VERSION 5.7 ;
  NOWIREEXTENSIONATPIN ON ;
  DIVIDERCHAR "/" ;
  BUSBITCHARS "[]" ;
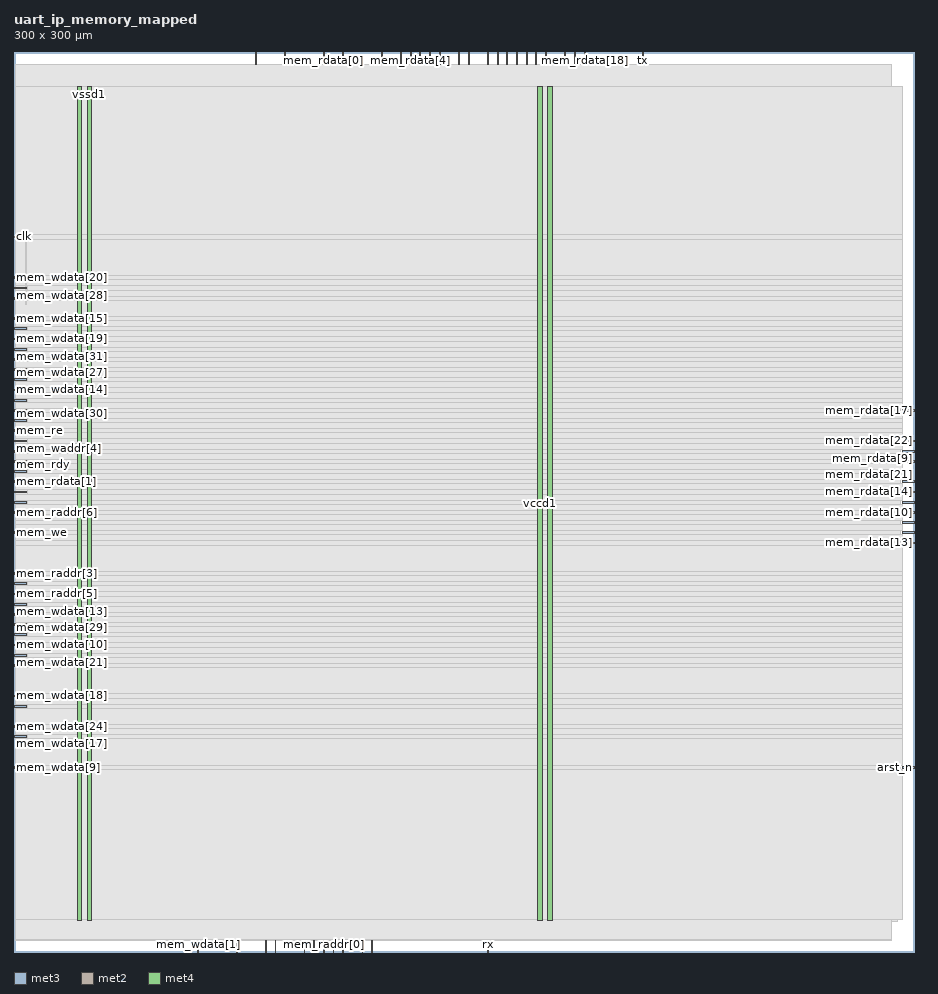
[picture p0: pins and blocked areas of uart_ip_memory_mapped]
MACRO uart_ip_memory_mapped
  CLASS BLOCK ;
  FOREIGN uart_ip_memory_mapped ;
  ORIGIN 0.000 0.000 ;
  SIZE 300.000 BY 300.000 ;
  PIN arst_n
    DIRECTION INPUT ;
    USE SIGNAL ;
    ANTENNAGATEAREA 0.682200 ;
    ANTENNADIFFAREA 0.434700 ;
    PORT
      LAYER met3 ;
        RECT 296.000 61.240 300.000 61.840 ;
    END
  END arst_n
  PIN clk
    DIRECTION INPUT ;
    USE SIGNAL ;
    ANTENNAGATEAREA 1.286700 ;
    ANTENNADIFFAREA 0.434700 ;
    PORT
      LAYER met3 ;
        RECT 0.000 238.040 4.000 238.640 ;
    END
  END clk
  PIN mem_raddr[0]
    DIRECTION OUTPUT ;
    USE SIGNAL ;
    ANTENNADIFFAREA 0.340600 ;
    PORT
      LAYER met2 ;
        RECT 103.130 0.000 103.410 4.000 ;
    END
  END mem_raddr[0]
  PIN mem_raddr[1]
    DIRECTION OUTPUT ;
    USE SIGNAL ;
    ANTENNADIFFAREA 0.340600 ;
    PORT
      LAYER met2 ;
        RECT 119.230 0.000 119.510 4.000 ;
    END
  END mem_raddr[1]
  PIN mem_raddr[2]
    DIRECTION OUTPUT ;
    USE SIGNAL ;
    ANTENNADIFFAREA 0.340600 ;
    PORT
      LAYER met2 ;
        RECT 109.570 0.000 109.850 4.000 ;
    END
  END mem_raddr[2]
  PIN mem_raddr[3]
    DIRECTION OUTPUT ;
    USE SIGNAL ;
    ANTENNADIFFAREA 0.340600 ;
    PORT
      LAYER met3 ;
        RECT 0.000 125.840 4.000 126.440 ;
    END
  END mem_raddr[3]
  PIN mem_raddr[4]
    DIRECTION OUTPUT ;
    USE SIGNAL ;
    ANTENNADIFFAREA 0.340600 ;
    PORT
      LAYER met3 ;
        RECT 0.000 149.640 4.000 150.240 ;
    END
  END mem_raddr[4]
  PIN mem_raddr[5]
    DIRECTION OUTPUT ;
    USE SIGNAL ;
    ANTENNADIFFAREA 0.340600 ;
    PORT
      LAYER met3 ;
        RECT 0.000 119.040 4.000 119.640 ;
    END
  END mem_raddr[5]
  PIN mem_raddr[6]
    DIRECTION OUTPUT ;
    USE SIGNAL ;
    ANTENNADIFFAREA 0.340600 ;
    PORT
      LAYER met3 ;
        RECT 0.000 146.240 4.000 146.840 ;
    END
  END mem_raddr[6]
  PIN mem_raddr[7]
    DIRECTION OUTPUT ;
    USE SIGNAL ;
    ANTENNADIFFAREA 0.340600 ;
    PORT
      LAYER met3 ;
        RECT 0.000 166.640 4.000 167.240 ;
    END
  END mem_raddr[7]
  PIN mem_rdata[0]
    DIRECTION INPUT ;
    USE SIGNAL ;
    ANTENNAGATEAREA 0.631200 ;
    ANTENNADIFFAREA 0.434700 ;
    PORT
      LAYER met2 ;
        RECT 103.130 296.000 103.410 300.000 ;
    END
  END mem_rdata[0]
  PIN mem_rdata[10]
    DIRECTION INPUT ;
    USE SIGNAL ;
    ANTENNAGATEAREA 0.631200 ;
    ANTENNADIFFAREA 0.434700 ;
    PORT
      LAYER met3 ;
        RECT 296.000 146.240 300.000 146.840 ;
    END
  END mem_rdata[10]
  PIN mem_rdata[11]
    DIRECTION INPUT ;
    USE SIGNAL ;
    ANTENNAGATEAREA 0.631200 ;
    ANTENNADIFFAREA 0.434700 ;
    PORT
      LAYER met2 ;
        RECT 161.090 296.000 161.370 300.000 ;
    END
  END mem_rdata[11]
  PIN mem_rdata[12]
    DIRECTION INPUT ;
    USE SIGNAL ;
    ANTENNAGATEAREA 0.631200 ;
    ANTENNADIFFAREA 0.434700 ;
    PORT
      LAYER met2 ;
        RECT 157.870 296.000 158.150 300.000 ;
    END
  END mem_rdata[12]
  PIN mem_rdata[13]
    DIRECTION INPUT ;
    USE SIGNAL ;
    ANTENNAGATEAREA 0.631200 ;
    ANTENNADIFFAREA 0.434700 ;
    PORT
      LAYER met3 ;
        RECT 296.000 136.040 300.000 136.640 ;
    END
  END mem_rdata[13]
  PIN mem_rdata[14]
    DIRECTION INPUT ;
    USE SIGNAL ;
    ANTENNAGATEAREA 0.631200 ;
    ANTENNADIFFAREA 0.434700 ;
    PORT
      LAYER met3 ;
        RECT 296.000 153.040 300.000 153.640 ;
    END
  END mem_rdata[14]
  PIN mem_rdata[15]
    DIRECTION INPUT ;
    USE SIGNAL ;
    ANTENNAGATEAREA 0.631200 ;
    ANTENNADIFFAREA 0.434700 ;
    PORT
      LAYER met2 ;
        RECT 151.430 296.000 151.710 300.000 ;
    END
  END mem_rdata[15]
  PIN mem_rdata[16]
    DIRECTION INPUT ;
    USE SIGNAL ;
    ANTENNAGATEAREA 0.631200 ;
    ANTENNADIFFAREA 0.434700 ;
    PORT
      LAYER met2 ;
        RECT 122.450 296.000 122.730 300.000 ;
    END
  END mem_rdata[16]
  PIN mem_rdata[17]
    DIRECTION INPUT ;
    USE SIGNAL ;
    ANTENNAGATEAREA 0.631200 ;
    ANTENNADIFFAREA 0.434700 ;
    PORT
      LAYER met3 ;
        RECT 296.000 180.240 300.000 180.840 ;
    END
  END mem_rdata[17]
  PIN mem_rdata[18]
    DIRECTION INPUT ;
    USE SIGNAL ;
    ANTENNAGATEAREA 0.631200 ;
    ANTENNADIFFAREA 0.434700 ;
    PORT
      LAYER met2 ;
        RECT 190.070 296.000 190.350 300.000 ;
    END
  END mem_rdata[18]
  PIN mem_rdata[19]
    DIRECTION INPUT ;
    USE SIGNAL ;
    ANTENNAGATEAREA 0.631200 ;
    ANTENNADIFFAREA 0.434700 ;
    PORT
      LAYER met2 ;
        RECT 164.310 296.000 164.590 300.000 ;
    END
  END mem_rdata[19]
  PIN mem_rdata[1]
    DIRECTION INPUT ;
    USE SIGNAL ;
    ANTENNAGATEAREA 0.631200 ;
    ANTENNADIFFAREA 0.434700 ;
    PORT
      LAYER met3 ;
        RECT 0.000 156.440 4.000 157.040 ;
    END
  END mem_rdata[1]
  PIN mem_rdata[20]
    DIRECTION INPUT ;
    USE SIGNAL ;
    ANTENNAGATEAREA 0.631200 ;
    ANTENNADIFFAREA 0.434700 ;
    PORT
      LAYER met2 ;
        RECT 170.750 296.000 171.030 300.000 ;
    END
  END mem_rdata[20]
  PIN mem_rdata[21]
    DIRECTION INPUT ;
    USE SIGNAL ;
    ANTENNAGATEAREA 0.631200 ;
    ANTENNADIFFAREA 0.434700 ;
    PORT
      LAYER met3 ;
        RECT 296.000 156.440 300.000 157.040 ;
    END
  END mem_rdata[21]
  PIN mem_rdata[22]
    DIRECTION INPUT ;
    USE SIGNAL ;
    ANTENNAGATEAREA 0.631200 ;
    ANTENNADIFFAREA 0.434700 ;
    PORT
      LAYER met3 ;
        RECT 296.000 170.040 300.000 170.640 ;
    END
  END mem_rdata[22]
  PIN mem_rdata[23]
    DIRECTION INPUT ;
    USE SIGNAL ;
    ANTENNAGATEAREA 0.631200 ;
    ANTENNADIFFAREA 0.434700 ;
    PORT
      LAYER met2 ;
        RECT 141.770 296.000 142.050 300.000 ;
    END
  END mem_rdata[23]
  PIN mem_rdata[24]
    DIRECTION INPUT ;
    USE SIGNAL ;
    ANTENNAGATEAREA 0.631200 ;
    ANTENNADIFFAREA 0.434700 ;
    PORT
      LAYER met2 ;
        RECT 128.890 296.000 129.170 300.000 ;
    END
  END mem_rdata[24]
  PIN mem_rdata[25]
    DIRECTION INPUT ;
    USE SIGNAL ;
    ANTENNAGATEAREA 0.631200 ;
    ANTENNADIFFAREA 0.434700 ;
    PORT
      LAYER met2 ;
        RECT 183.630 296.000 183.910 300.000 ;
    END
  END mem_rdata[25]
  PIN mem_rdata[26]
    DIRECTION INPUT ;
    USE SIGNAL ;
    ANTENNAGATEAREA 0.631200 ;
    ANTENNADIFFAREA 0.434700 ;
    PORT
      LAYER met2 ;
        RECT 186.850 296.000 187.130 300.000 ;
    END
  END mem_rdata[26]
  PIN mem_rdata[27]
    DIRECTION INPUT ;
    USE SIGNAL ;
    ANTENNAGATEAREA 0.631200 ;
    ANTENNADIFFAREA 0.434700 ;
    PORT
      LAYER met2 ;
        RECT 167.530 296.000 167.810 300.000 ;
    END
  END mem_rdata[27]
  PIN mem_rdata[28]
    DIRECTION INPUT ;
    USE SIGNAL ;
    ANTENNAGATEAREA 0.631200 ;
    ANTENNADIFFAREA 0.434700 ;
    PORT
      LAYER met2 ;
        RECT 173.970 296.000 174.250 300.000 ;
    END
  END mem_rdata[28]
  PIN mem_rdata[29]
    DIRECTION INPUT ;
    USE SIGNAL ;
    ANTENNAGATEAREA 0.631200 ;
    ANTENNADIFFAREA 0.434700 ;
    PORT
      LAYER met3 ;
        RECT 296.000 163.240 300.000 163.840 ;
    END
  END mem_rdata[29]
  PIN mem_rdata[2]
    DIRECTION INPUT ;
    USE SIGNAL ;
    ANTENNAGATEAREA 0.631200 ;
    ANTENNADIFFAREA 0.434700 ;
    PORT
      LAYER met3 ;
        RECT 296.000 142.840 300.000 143.440 ;
    END
  END mem_rdata[2]
  PIN mem_rdata[30]
    DIRECTION INPUT ;
    USE SIGNAL ;
    ANTENNAGATEAREA 0.631200 ;
    ANTENNADIFFAREA 0.434700 ;
    PORT
      LAYER met2 ;
        RECT 177.190 296.000 177.470 300.000 ;
    END
  END mem_rdata[30]
  PIN mem_rdata[31]
    DIRECTION INPUT ;
    USE SIGNAL ;
    ANTENNAGATEAREA 0.631200 ;
    ANTENNADIFFAREA 0.434700 ;
    PORT
      LAYER met2 ;
        RECT 138.550 296.000 138.830 300.000 ;
    END
  END mem_rdata[31]
  PIN mem_rdata[3]
    DIRECTION INPUT ;
    USE SIGNAL ;
    ANTENNAGATEAREA 0.631200 ;
    ANTENNADIFFAREA 0.434700 ;
    PORT
      LAYER met2 ;
        RECT 135.330 296.000 135.610 300.000 ;
    END
  END mem_rdata[3]
  PIN mem_rdata[4]
    DIRECTION INPUT ;
    USE SIGNAL ;
    ANTENNAGATEAREA 0.631200 ;
    ANTENNADIFFAREA 0.434700 ;
    PORT
      LAYER met2 ;
        RECT 132.110 296.000 132.390 300.000 ;
    END
  END mem_rdata[4]
  PIN mem_rdata[5]
    DIRECTION INPUT ;
    USE SIGNAL ;
    ANTENNAGATEAREA 0.631200 ;
    ANTENNADIFFAREA 0.434700 ;
    PORT
      LAYER met3 ;
        RECT 296.000 139.440 300.000 140.040 ;
    END
  END mem_rdata[5]
  PIN mem_rdata[6]
    DIRECTION INPUT ;
    USE SIGNAL ;
    ANTENNAGATEAREA 0.631200 ;
    ANTENNADIFFAREA 0.434700 ;
    PORT
      LAYER met3 ;
        RECT 296.000 149.640 300.000 150.240 ;
    END
  END mem_rdata[6]
  PIN mem_rdata[7]
    DIRECTION INPUT ;
    USE SIGNAL ;
    ANTENNAGATEAREA 0.631200 ;
    ANTENNADIFFAREA 0.434700 ;
    PORT
      LAYER met2 ;
        RECT 148.210 296.000 148.490 300.000 ;
    END
  END mem_rdata[7]
  PIN mem_rdata[8]
    DIRECTION INPUT ;
    USE SIGNAL ;
    ANTENNAGATEAREA 0.631200 ;
    ANTENNADIFFAREA 0.434700 ;
    PORT
      LAYER met2 ;
        RECT 109.570 296.000 109.850 300.000 ;
    END
  END mem_rdata[8]
  PIN mem_rdata[9]
    DIRECTION INPUT ;
    USE SIGNAL ;
    ANTENNAGATEAREA 0.631200 ;
    ANTENNADIFFAREA 0.434700 ;
    PORT
      LAYER met3 ;
        RECT 296.000 166.640 300.000 167.240 ;
    END
  END mem_rdata[9]
  PIN mem_rdy
    DIRECTION INPUT ;
    USE SIGNAL ;
    ANTENNAGATEAREA 0.631200 ;
    ANTENNADIFFAREA 0.434700 ;
    PORT
      LAYER met3 ;
        RECT 0.000 159.840 4.000 160.440 ;
    END
  END mem_rdy
  PIN mem_re
    DIRECTION OUTPUT ;
    USE SIGNAL ;
    ANTENNADIFFAREA 0.340600 ;
    PORT
      LAYER met3 ;
        RECT 0.000 173.440 4.000 174.040 ;
    END
  END mem_re
  PIN mem_waddr[0]
    DIRECTION OUTPUT ;
    USE SIGNAL ;
    ANTENNADIFFAREA 0.340600 ;
    PORT
      LAYER met2 ;
        RECT 106.350 0.000 106.630 4.000 ;
    END
  END mem_waddr[0]
  PIN mem_waddr[1]
    DIRECTION OUTPUT ;
    USE SIGNAL ;
    ANTENNADIFFAREA 0.340600 ;
    PORT
      LAYER met2 ;
        RECT 116.010 0.000 116.290 4.000 ;
    END
  END mem_waddr[1]
  PIN mem_waddr[2]
    DIRECTION OUTPUT ;
    USE SIGNAL ;
    ANTENNADIFFAREA 0.340600 ;
    PORT
      LAYER met2 ;
        RECT 96.690 0.000 96.970 4.000 ;
    END
  END mem_waddr[2]
  PIN mem_waddr[3]
    DIRECTION OUTPUT ;
    USE SIGNAL ;
    ANTENNADIFFAREA 0.340600 ;
    PORT
      LAYER met3 ;
        RECT 0.000 122.440 4.000 123.040 ;
    END
  END mem_waddr[3]
  PIN mem_waddr[4]
    DIRECTION OUTPUT ;
    USE SIGNAL ;
    ANTENNADIFFAREA 0.340600 ;
    PORT
      LAYER met3 ;
        RECT 0.000 170.040 4.000 170.640 ;
    END
  END mem_waddr[4]
  PIN mem_waddr[5]
    DIRECTION OUTPUT ;
    USE SIGNAL ;
    ANTENNADIFFAREA 0.340600 ;
    PORT
      LAYER met3 ;
        RECT 0.000 112.240 4.000 112.840 ;
    END
  END mem_waddr[5]
  PIN mem_waddr[6]
    DIRECTION OUTPUT ;
    USE SIGNAL ;
    ANTENNADIFFAREA 0.340600 ;
    PORT
      LAYER met3 ;
        RECT 0.000 153.040 4.000 153.640 ;
    END
  END mem_waddr[6]
  PIN mem_waddr[7]
    DIRECTION OUTPUT ;
    USE SIGNAL ;
    ANTENNADIFFAREA 0.340600 ;
    PORT
      LAYER met3 ;
        RECT 0.000 163.240 4.000 163.840 ;
    END
  END mem_waddr[7]
  PIN mem_wdata[0]
    DIRECTION OUTPUT ;
    USE SIGNAL ;
    ANTENNADIFFAREA 0.340600 ;
    PORT
      LAYER met2 ;
        RECT 99.910 0.000 100.190 4.000 ;
    END
  END mem_wdata[0]
  PIN mem_wdata[10]
    DIRECTION OUTPUT ;
    USE SIGNAL ;
    ANTENNADIFFAREA 0.340600 ;
    PORT
      LAYER met3 ;
        RECT 0.000 102.040 4.000 102.640 ;
    END
  END mem_wdata[10]
  PIN mem_wdata[11]
    DIRECTION OUTPUT ;
    USE SIGNAL ;
    ANTENNADIFFAREA 0.340600 ;
    PORT
      LAYER met3 ;
        RECT 0.000 217.640 4.000 218.240 ;
    END
  END mem_wdata[11]
  PIN mem_wdata[12]
    DIRECTION OUTPUT ;
    USE SIGNAL ;
    ANTENNADIFFAREA 0.340600 ;
    PORT
      LAYER met2 ;
        RECT 80.590 296.000 80.870 300.000 ;
    END
  END mem_wdata[12]
  PIN mem_wdata[13]
    DIRECTION OUTPUT ;
    USE SIGNAL ;
    ANTENNADIFFAREA 0.340600 ;
    PORT
      LAYER met3 ;
        RECT 0.000 115.640 4.000 116.240 ;
    END
  END mem_wdata[13]
  PIN mem_wdata[14]
    DIRECTION OUTPUT ;
    USE SIGNAL ;
    ANTENNADIFFAREA 0.340600 ;
    PORT
      LAYER met3 ;
        RECT 0.000 187.040 4.000 187.640 ;
    END
  END mem_wdata[14]
  PIN mem_wdata[15]
    DIRECTION OUTPUT ;
    USE SIGNAL ;
    ANTENNADIFFAREA 0.340600 ;
    PORT
      LAYER met3 ;
        RECT 0.000 210.840 4.000 211.440 ;
    END
  END mem_wdata[15]
  PIN mem_wdata[16]
    DIRECTION OUTPUT ;
    USE SIGNAL ;
    ANTENNADIFFAREA 0.340600 ;
    PORT
      LAYER met2 ;
        RECT 74.150 0.000 74.430 4.000 ;
    END
  END mem_wdata[16]
  PIN mem_wdata[17]
    DIRECTION OUTPUT ;
    USE SIGNAL ;
    ANTENNADIFFAREA 0.340600 ;
    PORT
      LAYER met3 ;
        RECT 0.000 71.440 4.000 72.040 ;
    END
  END mem_wdata[17]
  PIN mem_wdata[18]
    DIRECTION OUTPUT ;
    USE SIGNAL ;
    ANTENNADIFFAREA 0.340600 ;
    PORT
      LAYER met3 ;
        RECT 0.000 85.040 4.000 85.640 ;
    END
  END mem_wdata[18]
  PIN mem_wdata[19]
    DIRECTION OUTPUT ;
    USE SIGNAL ;
    ANTENNADIFFAREA 0.340600 ;
    PORT
      LAYER met3 ;
        RECT 0.000 204.040 4.000 204.640 ;
    END
  END mem_wdata[19]
  PIN mem_wdata[1]
    DIRECTION OUTPUT ;
    USE SIGNAL ;
    ANTENNADIFFAREA 0.340600 ;
    PORT
      LAYER met2 ;
        RECT 61.270 0.000 61.550 4.000 ;
    END
  END mem_wdata[1]
  PIN mem_wdata[20]
    DIRECTION OUTPUT ;
    USE SIGNAL ;
    ANTENNADIFFAREA 0.340600 ;
    PORT
      LAYER met3 ;
        RECT 0.000 224.440 4.000 225.040 ;
    END
  END mem_wdata[20]
  PIN mem_wdata[21]
    DIRECTION OUTPUT ;
    USE SIGNAL ;
    ANTENNADIFFAREA 0.340600 ;
    PORT
      LAYER met3 ;
        RECT 0.000 98.640 4.000 99.240 ;
    END
  END mem_wdata[21]
  PIN mem_wdata[22]
    DIRECTION OUTPUT ;
    USE SIGNAL ;
    ANTENNADIFFAREA 0.340600 ;
    PORT
      LAYER met3 ;
        RECT 0.000 183.640 4.000 184.240 ;
    END
  END mem_wdata[22]
  PIN mem_wdata[23]
    DIRECTION OUTPUT ;
    USE SIGNAL ;
    ANTENNADIFFAREA 0.340600 ;
    PORT
      LAYER met3 ;
        RECT 0.000 207.440 4.000 208.040 ;
    END
  END mem_wdata[23]
  PIN mem_wdata[24]
    DIRECTION OUTPUT ;
    USE SIGNAL ;
    ANTENNADIFFAREA 0.340600 ;
    PORT
      LAYER met3 ;
        RECT 0.000 74.840 4.000 75.440 ;
    END
  END mem_wdata[24]
  PIN mem_wdata[25]
    DIRECTION OUTPUT ;
    USE SIGNAL ;
    ANTENNADIFFAREA 0.340600 ;
    PORT
      LAYER met3 ;
        RECT 0.000 81.640 4.000 82.240 ;
    END
  END mem_wdata[25]
  PIN mem_wdata[26]
    DIRECTION OUTPUT ;
    USE SIGNAL ;
    ANTENNADIFFAREA 0.340600 ;
    PORT
      LAYER met3 ;
        RECT 0.000 95.240 4.000 95.840 ;
    END
  END mem_wdata[26]
  PIN mem_wdata[27]
    DIRECTION OUTPUT ;
    USE SIGNAL ;
    ANTENNADIFFAREA 0.340600 ;
    PORT
      LAYER met3 ;
        RECT 0.000 190.440 4.000 191.040 ;
    END
  END mem_wdata[27]
  PIN mem_wdata[28]
    DIRECTION OUTPUT ;
    USE SIGNAL ;
    ANTENNADIFFAREA 0.340600 ;
    PORT
      LAYER met3 ;
        RECT 0.000 221.040 4.000 221.640 ;
    END
  END mem_wdata[28]
  PIN mem_wdata[29]
    DIRECTION OUTPUT ;
    USE SIGNAL ;
    ANTENNADIFFAREA 0.340600 ;
    PORT
      LAYER met3 ;
        RECT 0.000 105.440 4.000 106.040 ;
    END
  END mem_wdata[29]
  PIN mem_wdata[2]
    DIRECTION OUTPUT ;
    USE SIGNAL ;
    ANTENNADIFFAREA 0.340600 ;
    PORT
      LAYER met2 ;
        RECT 87.030 0.000 87.310 4.000 ;
    END
  END mem_wdata[2]
  PIN mem_wdata[30]
    DIRECTION OUTPUT ;
    USE SIGNAL ;
    ANTENNADIFFAREA 0.340600 ;
    PORT
      LAYER met3 ;
        RECT 0.000 176.840 4.000 177.440 ;
    END
  END mem_wdata[30]
  PIN mem_wdata[31]
    DIRECTION OUTPUT ;
    USE SIGNAL ;
    ANTENNADIFFAREA 0.340600 ;
    PORT
      LAYER met3 ;
        RECT 0.000 200.640 4.000 201.240 ;
    END
  END mem_wdata[31]
  PIN mem_wdata[3]
    DIRECTION OUTPUT ;
    USE SIGNAL ;
    ANTENNADIFFAREA 0.340600 ;
    PORT
      LAYER met3 ;
        RECT 0.000 193.840 4.000 194.440 ;
    END
  END mem_wdata[3]
  PIN mem_wdata[4]
    DIRECTION OUTPUT ;
    USE SIGNAL ;
    ANTENNADIFFAREA 0.340600 ;
    PORT
      LAYER met2 ;
        RECT 90.250 296.000 90.530 300.000 ;
    END
  END mem_wdata[4]
  PIN mem_wdata[5]
    DIRECTION OUTPUT ;
    USE SIGNAL ;
    ANTENNADIFFAREA 0.340600 ;
    PORT
      LAYER met3 ;
        RECT 0.000 108.840 4.000 109.440 ;
    END
  END mem_wdata[5]
  PIN mem_wdata[6]
    DIRECTION OUTPUT ;
    USE SIGNAL ;
    ANTENNADIFFAREA 0.340600 ;
    PORT
      LAYER met3 ;
        RECT 0.000 180.240 4.000 180.840 ;
    END
  END mem_wdata[6]
  PIN mem_wdata[7]
    DIRECTION OUTPUT ;
    USE SIGNAL ;
    ANTENNADIFFAREA 0.340600 ;
    PORT
      LAYER met3 ;
        RECT 0.000 197.240 4.000 197.840 ;
    END
  END mem_wdata[7]
  PIN mem_wdata[8]
    DIRECTION OUTPUT ;
    USE SIGNAL ;
    ANTENNADIFFAREA 0.340600 ;
    PORT
      LAYER met2 ;
        RECT 83.810 0.000 84.090 4.000 ;
    END
  END mem_wdata[8]
  PIN mem_wdata[9]
    DIRECTION OUTPUT ;
    USE SIGNAL ;
    ANTENNADIFFAREA 0.340600 ;
    PORT
      LAYER met3 ;
        RECT 0.000 61.240 4.000 61.840 ;
    END
  END mem_wdata[9]
  PIN mem_we
    DIRECTION OUTPUT ;
    USE SIGNAL ;
    ANTENNADIFFAREA 0.340600 ;
    PORT
      LAYER met3 ;
        RECT 0.000 139.440 4.000 140.040 ;
    END
  END mem_we
  PIN rx
    DIRECTION INPUT ;
    USE SIGNAL ;
    ANTENNAGATEAREA 0.631200 ;
    ANTENNADIFFAREA 0.434700 ;
    PORT
      LAYER met2 ;
        RECT 157.870 0.000 158.150 4.000 ;
    END
  END rx
  PIN tx
    DIRECTION OUTPUT ;
    USE SIGNAL ;
    ANTENNADIFFAREA 1.782000 ;
    PORT
      LAYER met2 ;
        RECT 209.390 296.000 209.670 300.000 ;
    END
  END tx
  PIN vccd1
    DIRECTION INOUT ;
    USE POWER ;
    PORT
      LAYER met4 ;
        RECT 21.040 10.640 22.640 288.560 ;
    END
    PORT
      LAYER met4 ;
        RECT 174.640 10.640 176.240 288.560 ;
    END
  END vccd1
  PIN vssd1
    DIRECTION INOUT ;
    USE GROUND ;
    PORT
      LAYER met4 ;
        RECT 24.340 10.640 25.940 288.560 ;
    END
    PORT
      LAYER met4 ;
        RECT 177.940 10.640 179.540 288.560 ;
    END
  END vssd1
  OBS
      LAYER nwell ;
        RECT 5.330 10.760 294.590 288.440 ;
      LAYER li1 ;
        RECT 5.520 10.795 294.400 288.405 ;
      LAYER met1 ;
        RECT 4.210 10.240 294.400 288.560 ;
      LAYER met2 ;
        RECT 0.550 295.720 80.310 296.000 ;
        RECT 81.150 295.720 89.970 296.000 ;
        RECT 90.810 295.720 102.850 296.000 ;
        RECT 103.690 295.720 109.290 296.000 ;
        RECT 110.130 295.720 122.170 296.000 ;
        RECT 123.010 295.720 128.610 296.000 ;
        RECT 129.450 295.720 131.830 296.000 ;
        RECT 132.670 295.720 135.050 296.000 ;
        RECT 135.890 295.720 138.270 296.000 ;
        RECT 139.110 295.720 141.490 296.000 ;
        RECT 142.330 295.720 147.930 296.000 ;
        RECT 148.770 295.720 151.150 296.000 ;
        RECT 151.990 295.720 157.590 296.000 ;
        RECT 158.430 295.720 160.810 296.000 ;
        RECT 161.650 295.720 164.030 296.000 ;
        RECT 164.870 295.720 167.250 296.000 ;
        RECT 168.090 295.720 170.470 296.000 ;
        RECT 171.310 295.720 173.690 296.000 ;
        RECT 174.530 295.720 176.910 296.000 ;
        RECT 177.750 295.720 183.350 296.000 ;
        RECT 184.190 295.720 186.570 296.000 ;
        RECT 187.410 295.720 189.790 296.000 ;
        RECT 190.630 295.720 209.110 296.000 ;
        RECT 209.950 295.720 292.470 296.000 ;
        RECT 0.550 4.280 292.470 295.720 ;
        RECT 0.550 4.000 60.990 4.280 ;
        RECT 61.830 4.000 73.870 4.280 ;
        RECT 74.710 4.000 83.530 4.280 ;
        RECT 84.370 4.000 86.750 4.280 ;
        RECT 87.590 4.000 96.410 4.280 ;
        RECT 97.250 4.000 99.630 4.280 ;
        RECT 100.470 4.000 102.850 4.280 ;
        RECT 103.690 4.000 106.070 4.280 ;
        RECT 106.910 4.000 109.290 4.280 ;
        RECT 110.130 4.000 115.730 4.280 ;
        RECT 116.570 4.000 118.950 4.280 ;
        RECT 119.790 4.000 157.590 4.280 ;
        RECT 158.430 4.000 292.470 4.280 ;
      LAYER met3 ;
        RECT 0.525 239.040 296.000 288.485 ;
        RECT 4.400 237.640 296.000 239.040 ;
        RECT 0.525 225.440 296.000 237.640 ;
        RECT 4.400 224.040 296.000 225.440 ;
        RECT 0.525 222.040 296.000 224.040 ;
        RECT 4.400 220.640 296.000 222.040 ;
        RECT 0.525 218.640 296.000 220.640 ;
        RECT 4.400 217.240 296.000 218.640 ;
        RECT 0.525 211.840 296.000 217.240 ;
        RECT 4.400 210.440 296.000 211.840 ;
        RECT 0.525 208.440 296.000 210.440 ;
        RECT 4.400 207.040 296.000 208.440 ;
        RECT 0.525 205.040 296.000 207.040 ;
        RECT 4.400 203.640 296.000 205.040 ;
        RECT 0.525 201.640 296.000 203.640 ;
        RECT 4.400 200.240 296.000 201.640 ;
        RECT 0.525 198.240 296.000 200.240 ;
        RECT 4.400 196.840 296.000 198.240 ;
        RECT 0.525 194.840 296.000 196.840 ;
        RECT 4.400 193.440 296.000 194.840 ;
        RECT 0.525 191.440 296.000 193.440 ;
        RECT 4.400 190.040 296.000 191.440 ;
        RECT 0.525 188.040 296.000 190.040 ;
        RECT 4.400 186.640 296.000 188.040 ;
        RECT 0.525 184.640 296.000 186.640 ;
        RECT 4.400 183.240 296.000 184.640 ;
        RECT 0.525 181.240 296.000 183.240 ;
        RECT 4.400 179.840 295.600 181.240 ;
        RECT 0.525 177.840 296.000 179.840 ;
        RECT 4.400 176.440 296.000 177.840 ;
        RECT 0.525 174.440 296.000 176.440 ;
        RECT 4.400 173.040 296.000 174.440 ;
        RECT 0.525 171.040 296.000 173.040 ;
        RECT 4.400 169.640 295.600 171.040 ;
        RECT 0.525 167.640 296.000 169.640 ;
        RECT 4.400 166.240 295.600 167.640 ;
        RECT 0.525 164.240 296.000 166.240 ;
        RECT 4.400 162.840 295.600 164.240 ;
        RECT 0.525 160.840 296.000 162.840 ;
        RECT 4.400 159.440 296.000 160.840 ;
        RECT 0.525 157.440 296.000 159.440 ;
        RECT 4.400 156.040 295.600 157.440 ;
        RECT 0.525 154.040 296.000 156.040 ;
        RECT 4.400 152.640 295.600 154.040 ;
        RECT 0.525 150.640 296.000 152.640 ;
        RECT 4.400 149.240 295.600 150.640 ;
        RECT 0.525 147.240 296.000 149.240 ;
        RECT 4.400 145.840 295.600 147.240 ;
        RECT 0.525 143.840 296.000 145.840 ;
        RECT 0.525 142.440 295.600 143.840 ;
        RECT 0.525 140.440 296.000 142.440 ;
        RECT 4.400 139.040 295.600 140.440 ;
        RECT 0.525 137.040 296.000 139.040 ;
        RECT 0.525 135.640 295.600 137.040 ;
        RECT 0.525 126.840 296.000 135.640 ;
        RECT 4.400 125.440 296.000 126.840 ;
        RECT 0.525 123.440 296.000 125.440 ;
        RECT 4.400 122.040 296.000 123.440 ;
        RECT 0.525 120.040 296.000 122.040 ;
        RECT 4.400 118.640 296.000 120.040 ;
        RECT 0.525 116.640 296.000 118.640 ;
        RECT 4.400 115.240 296.000 116.640 ;
        RECT 0.525 113.240 296.000 115.240 ;
        RECT 4.400 111.840 296.000 113.240 ;
        RECT 0.525 109.840 296.000 111.840 ;
        RECT 4.400 108.440 296.000 109.840 ;
        RECT 0.525 106.440 296.000 108.440 ;
        RECT 4.400 105.040 296.000 106.440 ;
        RECT 0.525 103.040 296.000 105.040 ;
        RECT 4.400 101.640 296.000 103.040 ;
        RECT 0.525 99.640 296.000 101.640 ;
        RECT 4.400 98.240 296.000 99.640 ;
        RECT 0.525 96.240 296.000 98.240 ;
        RECT 4.400 94.840 296.000 96.240 ;
        RECT 0.525 86.040 296.000 94.840 ;
        RECT 4.400 84.640 296.000 86.040 ;
        RECT 0.525 82.640 296.000 84.640 ;
        RECT 4.400 81.240 296.000 82.640 ;
        RECT 0.525 75.840 296.000 81.240 ;
        RECT 4.400 74.440 296.000 75.840 ;
        RECT 0.525 72.440 296.000 74.440 ;
        RECT 4.400 71.040 296.000 72.440 ;
        RECT 0.525 62.240 296.000 71.040 ;
        RECT 4.400 60.840 295.600 62.240 ;
        RECT 0.525 10.715 296.000 60.840 ;
      LAYER met4 ;
        RECT 3.975 215.735 4.305 238.505 ;
  END
END uart_ip_memory_mapped
END LIBRARY

